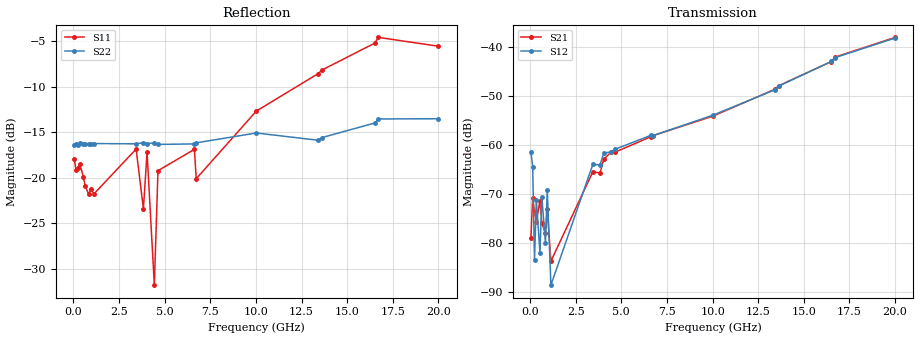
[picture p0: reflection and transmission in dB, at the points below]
!  2-Port S-parameters saved by WinCal
! VAR MeasName=S-Parameters (CALIBRATED_DATA) read from VNA (E8364A)
! VAR MeasDate=10/28/2010 3:35:00 PM
! VAR NAME=5-1you
! VAR FILENAME=5-1you.s2p
! VAR DATE=10/28/2010 3:35:00 PM
! VAR PHYS_PORTS=1,2
# Hz S RI R 50
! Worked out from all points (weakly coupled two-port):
!   201 points, 45 MHz to 20 GHz, reference 50 ohm
!   highest |S21| = -37.96 dB at 20 GHz (marker M1); lowest = -83.6 dB at 1.143 GHz (marker M2)
!   lowest |S11| = -31.8 dB at 4.435 GHz (marker M3), VSWR 1.05, Z = 50.4 - j2.54 ohm
!   |S11| at or under -10 dB: start of sweep to 11.87 GHz; 14.08525 GHz to 14.13933 GHz (54.08 MHz wide, 0.383 % of centre)
!   |S22| runs from -16.6 to -12.7 dB; largest |S21 - S12| = 0.00092
!   S11 on the Smith chart (normalised r, x): 45 MHz: 1.29, -0.03; 6.63 GHz: 1.00, -0.29; 13.61 GHz: 0.47, -0.26; 16.51 GHz: 0.29, +0.04; 20 GHz: 0.37, +0.41
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4.5e7  0.1265 -0.0105  9.67e-05 5.77e-05  -0.00072 0.000476  -0.1518 -0.00126
1.44775e8  0.1099 -0.00974  0.000273 0.000101  0.00044 0.000422  -0.1532 -0.000408
2.4455e8  0.1124 -0.00899  0.000162 0.00013  5.13e-05 4.33e-05  -0.1521 0.00109
3.44325e8  0.1182 -0.0176  0.000124 0.000111  0.000274 -4.92e-05  -0.1543 -0.00134
5.43875e8  0.1 -0.0173  0.000263 7.02e-05  6.76e-05 -4.33e-05  -0.1538 0.000339
6.4365e8  0.0889 -0.015  0.000155 -4.98e-05  0.000267 -0.000136  -0.1523 0.00112
8.432e8  0.0771 -0.0242  0.000126 -1.55e-05  7.35e-05 7.01e-05  -0.154 0.000821
9.42975e8  0.0828 -0.0244  0.000216 -5.53e-05  0.00035 1.12e-05  -0.1538 0.00102
1.142525e9  0.0794 -0.0194  6.29e-05 -1.98e-05  3.68e-05 -7.59e-06  -0.1541 0.00233
3.43735e9  0.1059 -0.0972  3.89e-06 0.000537  -1.92e-05 0.000639  -0.1535 0.00564
3.83645e9  0.0418 -0.0529  -3.26e-05 0.000523  0.000127 0.000622  -0.1558 0.00663
4.036e9  0.0743 -0.1164  7.91e-06 0.000722  4.64e-05 0.000832  -0.1538 0.00427
4.4351e9  0.00467 -0.0252  -8.36e-05 0.000852  8.68e-05 0.000856  -0.1555 0.00422
4.63465e9  0.0465 -0.0989  4.87e-05 0.000849  0.0001 0.000905  -0.1524 0.00134
6.63015e9  0.0204 -0.1417  0.000222 0.00121  3.58e-05 0.00127  -0.1534 0.000866
6.729925e9  0.0125 -0.0979  0.000125 0.00125  0.000218 0.00124  -0.1555 0.00173
1.00225e10  -0.1262 -0.1953  0.00036 0.00196  0.000332 0.00201  -0.1761 0.00586
1.341485e10  -0.2443 -0.2832  0.000152 0.00374  0.000354 0.00368  -0.1591 0.0221
1.36144e10  -0.3167 -0.2293  0.000203 0.00406  0.000334 0.00401  -0.1651 0.0194
1.650788e10  -0.5476 0.0479  0.00309 0.00648  0.0031 0.00649  -0.1996 0.0108
1.670742e10  -0.5823 0.1049  0.00352 0.00715  0.00356 0.00702  -0.2098 0.0166
2e10  -0.3444 0.4015  0.0101 0.00764  0.00996 0.00751  -0.2035 0.056
